VERSION 5.7 ;
  NOWIREEXTENSIONATPIN ON ;
  DIVIDERCHAR "/" ;
  BUSBITCHARS "[]" ;
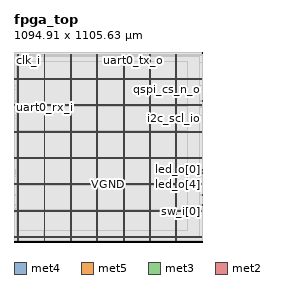
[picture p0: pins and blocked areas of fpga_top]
MACRO fpga_top
  CLASS BLOCK ;
  FOREIGN fpga_top ;
  ORIGIN 0.000 0.000 ;
  SIZE 1094.915 BY 1105.635 ;
  PIN VGND
    DIRECTION INOUT ;
    USE GROUND ;
    PORT
      LAYER met4 ;
        RECT 24.340 10.640 25.940 1093.680 ;
    END
    PORT
      LAYER met4 ;
        RECT 177.940 10.640 179.540 1093.680 ;
    END
    PORT
      LAYER met4 ;
        RECT 331.540 10.640 333.140 1093.680 ;
    END
    PORT
      LAYER met4 ;
        RECT 485.140 10.640 486.740 1093.680 ;
    END
    PORT
      LAYER met4 ;
        RECT 638.740 10.640 640.340 1093.680 ;
    END
    PORT
      LAYER met4 ;
        RECT 792.340 10.640 793.940 1093.680 ;
    END
    PORT
      LAYER met4 ;
        RECT 945.940 10.640 947.540 1093.680 ;
    END
    PORT
      LAYER met5 ;
        RECT 5.520 30.030 1089.280 31.630 ;
    END
    PORT
      LAYER met5 ;
        RECT 5.520 183.210 1089.280 184.810 ;
    END
    PORT
      LAYER met5 ;
        RECT 5.520 336.390 1089.280 337.990 ;
    END
    PORT
      LAYER met5 ;
        RECT 5.520 489.570 1089.280 491.170 ;
    END
    PORT
      LAYER met5 ;
        RECT 5.520 642.750 1089.280 644.350 ;
    END
    PORT
      LAYER met5 ;
        RECT 5.520 795.930 1089.280 797.530 ;
    END
    PORT
      LAYER met5 ;
        RECT 5.520 949.110 1089.280 950.710 ;
    END
  END VGND
  PIN VPWR
    DIRECTION INOUT ;
    USE POWER ;
    PORT
      LAYER met4 ;
        RECT 21.040 10.640 22.640 1093.680 ;
    END
    PORT
      LAYER met4 ;
        RECT 174.640 10.640 176.240 1093.680 ;
    END
    PORT
      LAYER met4 ;
        RECT 328.240 10.640 329.840 1093.680 ;
    END
    PORT
      LAYER met4 ;
        RECT 481.840 10.640 483.440 1093.680 ;
    END
    PORT
      LAYER met4 ;
        RECT 635.440 10.640 637.040 1093.680 ;
    END
    PORT
      LAYER met4 ;
        RECT 789.040 10.640 790.640 1093.680 ;
    END
    PORT
      LAYER met4 ;
        RECT 942.640 10.640 944.240 1093.680 ;
    END
    PORT
      LAYER met5 ;
        RECT 5.520 26.730 1089.280 28.330 ;
    END
    PORT
      LAYER met5 ;
        RECT 5.520 179.910 1089.280 181.510 ;
    END
    PORT
      LAYER met5 ;
        RECT 5.520 333.090 1089.280 334.690 ;
    END
    PORT
      LAYER met5 ;
        RECT 5.520 486.270 1089.280 487.870 ;
    END
    PORT
      LAYER met5 ;
        RECT 5.520 639.450 1089.280 641.050 ;
    END
    PORT
      LAYER met5 ;
        RECT 5.520 792.630 1089.280 794.230 ;
    END
    PORT
      LAYER met5 ;
        RECT 5.520 945.810 1089.280 947.410 ;
    END
  END VPWR
  PIN clk_i
    DIRECTION INPUT ;
    USE SIGNAL ;
    ANTENNAGATEAREA 0.852000 ;
    PORT
      LAYER met3 ;
        RECT 0.000 1086.680 0.600 1087.280 ;
    END
  END clk_i
  PIN i2c_scl_io
    DIRECTION INOUT ;
    USE SIGNAL ;
    ANTENNADIFFAREA 0.445500 ;
    PORT
      LAYER met3 ;
        RECT 1094.315 718.120 1094.915 718.720 ;
    END
  END i2c_scl_io
  PIN i2c_sda_io
    DIRECTION INOUT ;
    USE SIGNAL ;
    ANTENNAGATEAREA 0.994500 ;
    ANTENNADIFFAREA 0.891000 ;
    PORT
      LAYER met3 ;
        RECT 1094.315 737.160 1094.915 737.760 ;
    END
  END i2c_sda_io
  PIN led_o[0]
    DIRECTION OUTPUT ;
    USE SIGNAL ;
    ANTENNADIFFAREA 0.702900 ;
    PORT
      LAYER met3 ;
        RECT 1094.315 418.920 1094.915 419.520 ;
    END
  END led_o[0]
  PIN led_o[1]
    DIRECTION OUTPUT ;
    USE SIGNAL ;
    ANTENNADIFFAREA 0.702900 ;
    PORT
      LAYER met3 ;
        RECT 1094.315 393.080 1094.915 393.680 ;
    END
  END led_o[1]
  PIN led_o[2]
    DIRECTION OUTPUT ;
    USE SIGNAL ;
    ANTENNADIFFAREA 0.702900 ;
    PORT
      LAYER met3 ;
        RECT 1094.315 412.120 1094.915 412.720 ;
    END
  END led_o[2]
  PIN led_o[3]
    DIRECTION OUTPUT ;
    USE SIGNAL ;
    ANTENNADIFFAREA 0.702900 ;
    PORT
      LAYER met3 ;
        RECT 1094.315 405.320 1094.915 405.920 ;
    END
  END led_o[3]
  PIN led_o[4]
    DIRECTION OUTPUT ;
    USE SIGNAL ;
    ANTENNADIFFAREA 0.702900 ;
    PORT
      LAYER met3 ;
        RECT 1094.315 382.200 1094.915 382.800 ;
    END
  END led_o[4]
  PIN led_o[5]
    DIRECTION OUTPUT ;
    USE SIGNAL ;
    ANTENNADIFFAREA 0.702900 ;
    PORT
      LAYER met3 ;
        RECT 1094.315 416.200 1094.915 416.800 ;
    END
  END led_o[5]
  PIN led_o[6]
    DIRECTION OUTPUT ;
    USE SIGNAL ;
    ANTENNADIFFAREA 0.702900 ;
    PORT
      LAYER met3 ;
        RECT 1094.315 397.160 1094.915 397.760 ;
    END
  END led_o[6]
  PIN led_o[7]
    DIRECTION OUTPUT ;
    USE SIGNAL ;
    ANTENNADIFFAREA 0.702900 ;
    PORT
      LAYER met3 ;
        RECT 1094.315 401.240 1094.915 401.840 ;
    END
  END led_o[7]
  PIN qspi_cs_n_o
    DIRECTION OUTPUT ;
    USE SIGNAL ;
    ANTENNADIFFAREA 0.702900 ;
    PORT
      LAYER met3 ;
        RECT 1094.315 885.400 1094.915 886.000 ;
    END
  END qspi_cs_n_o
  PIN qspi_dq_io[0]
    DIRECTION INOUT ;
    USE SIGNAL ;
    ANTENNAGATEAREA 0.126000 ;
    ANTENNADIFFAREA 0.891000 ;
    PORT
      LAYER met3 ;
        RECT 1094.315 817.400 1094.915 818.000 ;
    END
  END qspi_dq_io[0]
  PIN qspi_dq_io[1]
    DIRECTION INOUT ;
    USE SIGNAL ;
    ANTENNAGATEAREA 0.252000 ;
    ANTENNADIFFAREA 0.891000 ;
    PORT
      LAYER met3 ;
        RECT 1094.315 818.760 1094.915 819.360 ;
    END
  END qspi_dq_io[1]
  PIN qspi_dq_io[2]
    DIRECTION INOUT ;
    USE SIGNAL ;
    ANTENNAGATEAREA 0.126000 ;
    ANTENNADIFFAREA 0.891000 ;
    PORT
      LAYER met3 ;
        RECT 1094.315 820.120 1094.915 820.720 ;
    END
  END qspi_dq_io[2]
  PIN qspi_dq_io[3]
    DIRECTION INOUT ;
    USE SIGNAL ;
    ANTENNAGATEAREA 0.126000 ;
    ANTENNADIFFAREA 0.891000 ;
    PORT
      LAYER met3 ;
        RECT 1094.315 821.480 1094.915 822.080 ;
    END
  END qspi_dq_io[3]
  PIN qspi_sck_o
    DIRECTION OUTPUT ;
    USE SIGNAL ;
    ANTENNADIFFAREA 0.702900 ;
    PORT
      LAYER met3 ;
        RECT 1094.315 908.520 1094.915 909.120 ;
    END
  END qspi_sck_o
  PIN rst_ni
    DIRECTION INPUT ;
    USE SIGNAL ;
    ANTENNAGATEAREA 0.159000 ;
    PORT
      LAYER met3 ;
        RECT 1094.315 273.400 1094.915 274.000 ;
    END
  END rst_ni
  PIN sw_i[0]
    DIRECTION INPUT ;
    USE SIGNAL ;
    ANTENNAGATEAREA 0.213000 ;
    PORT
      LAYER met3 ;
        RECT 1094.315 176.840 1094.915 177.440 ;
    END
  END sw_i[0]
  PIN sw_i[1]
    DIRECTION INPUT ;
    USE SIGNAL ;
    ANTENNAGATEAREA 0.213000 ;
    PORT
      LAYER met3 ;
        RECT 1094.315 194.520 1094.915 195.120 ;
    END
  END sw_i[1]
  PIN sw_i[2]
    DIRECTION INPUT ;
    USE SIGNAL ;
    ANTENNAGATEAREA 0.213000 ;
    PORT
      LAYER met3 ;
        RECT 1094.315 183.640 1094.915 184.240 ;
    END
  END sw_i[2]
  PIN sw_i[3]
    DIRECTION INPUT ;
    USE SIGNAL ;
    ANTENNAGATEAREA 0.213000 ;
    PORT
      LAYER met3 ;
        RECT 1094.315 190.440 1094.915 191.040 ;
    END
  END sw_i[3]
  PIN sw_i[4]
    DIRECTION INPUT ;
    USE SIGNAL ;
    ANTENNAGATEAREA 0.213000 ;
    PORT
      LAYER met3 ;
        RECT 1094.315 214.920 1094.915 215.520 ;
    END
  END sw_i[4]
  PIN sw_i[5]
    DIRECTION INPUT ;
    USE SIGNAL ;
    ANTENNAGATEAREA 0.213000 ;
    PORT
      LAYER met3 ;
        RECT 1094.315 187.720 1094.915 188.320 ;
    END
  END sw_i[5]
  PIN sw_i[6]
    DIRECTION INPUT ;
    USE SIGNAL ;
    ANTENNAGATEAREA 0.213000 ;
    PORT
      LAYER met3 ;
        RECT 1094.315 179.560 1094.915 180.160 ;
    END
  END sw_i[6]
  PIN sw_i[7]
    DIRECTION INPUT ;
    USE SIGNAL ;
    ANTENNAGATEAREA 0.213000 ;
    PORT
      LAYER met3 ;
        RECT 1094.315 171.400 1094.915 172.000 ;
    END
  END sw_i[7]
  PIN uart0_rx_i
    DIRECTION INPUT ;
    USE SIGNAL ;
    ANTENNAGATEAREA 0.159000 ;
    PORT
      LAYER met3 ;
        RECT 0.000 784.760 0.600 785.360 ;
    END
  END uart0_rx_i
  PIN uart0_tx_o
    DIRECTION OUTPUT ;
    USE SIGNAL ;
    ANTENNADIFFAREA 0.702900 ;
    PORT
      LAYER met2 ;
        RECT 694.690 1105.355 694.970 1105.635 ;
    END
  END uart0_tx_o
  PIN uart1_rx_i
    DIRECTION INPUT ;
    USE SIGNAL ;
    ANTENNAGATEAREA 0.159000 ;
    PORT
      LAYER met3 ;
        RECT 0.000 1043.160 0.600 1043.760 ;
    END
  END uart1_rx_i
  PIN uart1_tx_o
    DIRECTION OUTPUT ;
    USE SIGNAL ;
    ANTENNADIFFAREA 0.702900 ;
    PORT
      LAYER met2 ;
        RECT 944.930 1105.355 945.210 1105.635 ;
    END
  END uart1_tx_o
  OBS
      LAYER nwell ;
        RECT 5.330 10.795 1089.470 1093.525 ;
      LAYER li1 ;
        RECT 5.520 10.795 1089.280 1093.525 ;
      LAYER met1 ;
        RECT 1.450 10.640 1092.890 1093.680 ;
      LAYER met2 ;
        RECT 1.470 1105.075 694.410 1105.355 ;
        RECT 695.250 1105.075 944.650 1105.355 ;
        RECT 945.490 1105.075 1092.870 1105.355 ;
        RECT 1.470 10.695 1092.870 1105.075 ;
      LAYER met3 ;
        RECT 0.600 1087.680 1094.315 1093.605 ;
        RECT 1.000 1086.280 1094.315 1087.680 ;
        RECT 0.600 1044.160 1094.315 1086.280 ;
        RECT 1.000 1042.760 1094.315 1044.160 ;
        RECT 0.600 909.520 1094.315 1042.760 ;
        RECT 0.600 908.120 1093.915 909.520 ;
        RECT 0.600 886.400 1094.315 908.120 ;
        RECT 0.600 885.000 1093.915 886.400 ;
        RECT 0.600 822.480 1094.315 885.000 ;
        RECT 0.600 817.000 1093.915 822.480 ;
        RECT 0.600 785.760 1094.315 817.000 ;
        RECT 1.000 784.360 1094.315 785.760 ;
        RECT 0.600 738.160 1094.315 784.360 ;
        RECT 0.600 736.760 1093.915 738.160 ;
        RECT 0.600 719.120 1094.315 736.760 ;
        RECT 0.600 717.720 1093.915 719.120 ;
        RECT 0.600 419.920 1094.315 717.720 ;
        RECT 0.600 418.520 1093.915 419.920 ;
        RECT 0.600 417.200 1094.315 418.520 ;
        RECT 0.600 415.800 1093.915 417.200 ;
        RECT 0.600 413.120 1094.315 415.800 ;
        RECT 0.600 411.720 1093.915 413.120 ;
        RECT 0.600 406.320 1094.315 411.720 ;
        RECT 0.600 404.920 1093.915 406.320 ;
        RECT 0.600 402.240 1094.315 404.920 ;
        RECT 0.600 400.840 1093.915 402.240 ;
        RECT 0.600 398.160 1094.315 400.840 ;
        RECT 0.600 396.760 1093.915 398.160 ;
        RECT 0.600 394.080 1094.315 396.760 ;
        RECT 0.600 392.680 1093.915 394.080 ;
        RECT 0.600 383.200 1094.315 392.680 ;
        RECT 0.600 381.800 1093.915 383.200 ;
        RECT 0.600 274.400 1094.315 381.800 ;
        RECT 0.600 273.000 1093.915 274.400 ;
        RECT 0.600 215.920 1094.315 273.000 ;
        RECT 0.600 214.520 1093.915 215.920 ;
        RECT 0.600 195.520 1094.315 214.520 ;
        RECT 0.600 194.120 1093.915 195.520 ;
        RECT 0.600 191.440 1094.315 194.120 ;
        RECT 0.600 190.040 1093.915 191.440 ;
        RECT 0.600 188.720 1094.315 190.040 ;
        RECT 0.600 187.320 1093.915 188.720 ;
        RECT 0.600 184.640 1094.315 187.320 ;
        RECT 0.600 183.240 1093.915 184.640 ;
        RECT 0.600 180.560 1094.315 183.240 ;
        RECT 0.600 179.160 1093.915 180.560 ;
        RECT 0.600 177.840 1094.315 179.160 ;
        RECT 0.600 176.440 1093.915 177.840 ;
        RECT 0.600 172.400 1094.315 176.440 ;
        RECT 0.600 171.000 1093.915 172.400 ;
        RECT 0.600 10.715 1094.315 171.000 ;
      LAYER met4 ;
        RECT 12.750 34.175 20.640 1076.945 ;
        RECT 23.040 34.175 23.940 1076.945 ;
        RECT 26.340 34.175 174.240 1076.945 ;
        RECT 176.640 34.175 177.540 1076.945 ;
        RECT 179.940 34.175 327.840 1076.945 ;
        RECT 330.240 34.175 331.140 1076.945 ;
        RECT 333.540 34.175 481.440 1076.945 ;
        RECT 483.840 34.175 484.740 1076.945 ;
        RECT 487.140 34.175 635.040 1076.945 ;
        RECT 637.440 34.175 638.340 1076.945 ;
        RECT 640.740 34.175 788.640 1076.945 ;
        RECT 791.040 34.175 791.940 1076.945 ;
        RECT 794.340 34.175 942.240 1076.945 ;
        RECT 944.640 34.175 945.540 1076.945 ;
        RECT 947.940 34.175 1077.025 1076.945 ;
      LAYER met5 ;
        RECT 12.540 952.310 1008.660 1049.700 ;
        RECT 12.540 799.130 1008.660 944.210 ;
        RECT 12.540 645.950 1008.660 791.030 ;
        RECT 12.540 492.770 1008.660 637.850 ;
        RECT 12.540 339.590 1008.660 484.670 ;
        RECT 12.540 186.410 1008.660 331.490 ;
        RECT 12.540 68.900 1008.660 178.310 ;
  END
END fpga_top
END LIBRARY

